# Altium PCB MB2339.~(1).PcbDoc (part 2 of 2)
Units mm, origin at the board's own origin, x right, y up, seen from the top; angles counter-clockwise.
Board outline 43 x 47 mm, 4 copper layers (Top Layer, Signal Layer 1, Signal Layer 2, Bottom Layer), stack 1.539 mm thick; 100 components, 80 nets, 370 pads, 542 vias.

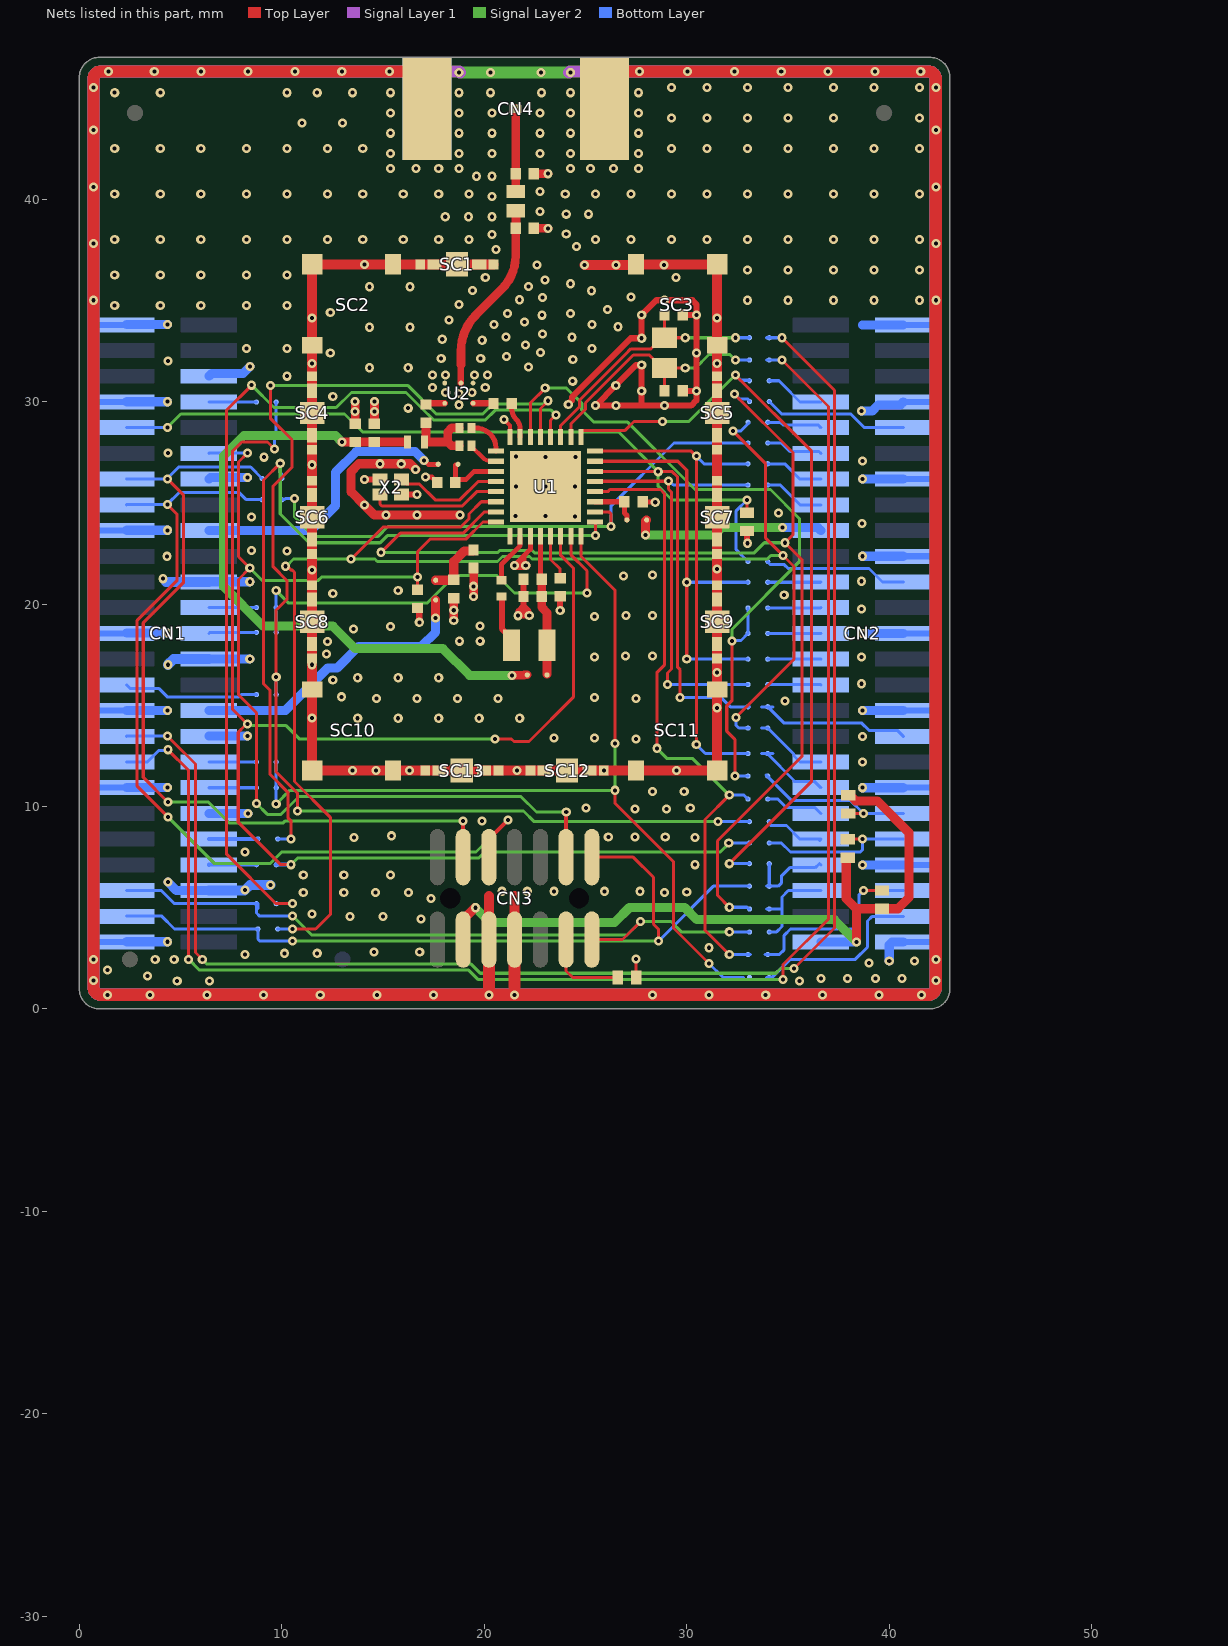
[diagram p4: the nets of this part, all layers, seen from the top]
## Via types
v1: diameter 0.45, hole 0.2, Top Layer to Bottom Layer, tented both sides, 542 vias

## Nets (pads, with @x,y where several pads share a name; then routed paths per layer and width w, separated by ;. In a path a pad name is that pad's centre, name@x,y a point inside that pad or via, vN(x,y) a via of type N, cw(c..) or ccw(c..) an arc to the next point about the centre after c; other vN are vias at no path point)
GND: C1.1 C2.1 C3.1 C4.2 C7.2 C8.1 C9.1 C10.1 C11.2 C12.1 C13.1 C14.1 C15.1 C16.2 CN1.1 CN1.6 CN1.7 CN1.14 CN1.17 CN1.22 CN1.25 CN1.28 CN1.31 CN1.34 CN1.37 CN1.40 CN1.46 CN1.49 CN2.2 CN2.8 CN2.14 CN2.20 CN2.26 CN2.32 CN2.38 CN2.44 CN2.50 CN3.5 CN3.7 CN4.2 CN4.3 CN4.4 CN4.5 R1.1 R5.1 SC1.1 SC2.1 SC3.1 SC4.1 SC5.1 SC6.1 SC7.1 SC8.1 SC9.1 SC10.1 SC11.1 SC12.1 SC13.1 U1.16 U1.27 U1.33 U2.B1 U2.B3 X2.2 X2.4 | length 913.3
  Top Layer w0.15: R5.1@27.5,1.55 v1(27.5,2.475)
  Top Layer w0.2: v1(20.975,29.12) 21.275,28.82 U1.16@21.275,28.25
  Top Layer w0.25: v1(17.1,26.263) 17.412,26.263 17.52,26.155 17.545,26.155 17.675,26.025 C9.1@17.675,26 ; v1@21.538,21.938 v1(21.5,21.9) 21.5,21.925 21.95,22.375 ; v1(22.05,21.9) 21.95,22 21.95,22.375 ; U1.27@22.275,23.35 22.275,22.7 21.95,22.375 ; C10.1@27.82,25.05 27.832,25.037 28.433,25.037 v1(28.445,25.025)
  Top Layer w0.3: v1@14.085,26.15 X2.4@14.855,26.15 ; X2.2@15.905,25.4 16.675,25.4 v1(16.68,25.405) ; v1(16.791,19.097) C15.1@16.791,19.802 ; C13.1@21.941,21.222 C16.2@21.941,20.372 21.941,19.885 ; v1@22.221,19.422 21.941,19.422 ; v1(22.221,19.428) 22.192,19.457 22.192,19.563 22.187,19.568 22.187,19.639 21.941,19.885 ; v1(23.75,19.67) C12.1@23.75,20.375 ; v1(24.15,29.85) 24.15,29.882 24.325,30.057 24.325,30.216 27.234,33.125 v1(27.775,33.125) v1(27.775,34.275) 28.5,35 v1(28.9,35) 30.275,35 30.475,34.8 v1(30.475,34.275) ; C4.2@29.8,30.525 v1(30.475,30.525) ; C3.1@29.8,34.275 v1(30.475,34.275) ; v1(32.992,23.002) 32.984,23.01 32.984,23.596 R1.1@33.023,23.635 ; 21.941,19.422 21.941,19.885 ; 21.941,19.422 v1(21.662,19.422) 21.69,19.451 21.69,19.557 21.696,19.562 21.696,19.645 21.935,19.885 21.941,19.885 ; 27.7,29.8 27.775,29.875 v1(27.775,30.525) v1(27.775,31.8) 27.766,31.791 27.491,31.791 v1(26.496,30.796) v1(25.5,29.8) v1(26.5,29.8) 27.7,29.8 ; 27.7,29.8 v1(28.9,29.8) 30.214,29.8 30.475,30.061 v1(30.475,30.525) ; v1(30.475,30.525) v1(30.475,32.4) v1(30.475,34.275)
  Top Layer w0.43: C7.2@13.625,28.9 v1(13.625,29.5) v1(13.625,30) ; C8.1@14.575,28.9 v1(14.575,29.5) v1(14.575,30) ; v1(18.493,19.191) v1(18.493,19.691) C14.1@18.493,20.291 ; v1(19.475,20.375) v1(19.475,20.875) C11.2@19.475,21.775 ; C2.1@22.45,38.55 v1(23.155,38.55) ; C1.1@22.45,41.25 v1(23.155,41.25)
  Top Layer w0.45: v1(14.08,26.145) v1@14.085,26.15 ; v1@14.855,26.92 v1(14.85,26.925) ; v1@16.614,26.646 16.335,26.925 v1(15.9,26.925) v1(14.85,26.925) ; v1(18.797,24.393) 18.791,24.387 v1(16.68,24.387) v1(15.155,24.387) 14.58,24.387 v1(14.08,24.887) 13.425,25.542 13.425,26.542 13.809,26.925 v1(14.85,26.925) ; v1(21.5,21.9) v1(22.05,21.9)
  Top Layer w0.5: SC8.1@11.5,20.5 SC6.1@11.5,22.468 SC6.1@11.5,23.178 SC6.1@11.5,24.278 SC6.1@11.5,25.378 SC6.1@11.5,26.088 v1(11.5,26.875) SC4.1@11.5,27.623 SC4.1@11.5,28.333 11.5,29.375 SC4.1@11.5,29.433 SC4.1@11.5,30.533 SC4.1@11.5,31.243 v1(11.5,31.875) SC2.1@11.5,32.775 v1(11.5,34.125) SC2.1@11.5,36.775 SC2.1@15.5,36.775 SC1.1@16.94,36.775 ; 11.5,20.655 11.5,19.555 v1(11.5,17) SC10.1@11.5,15.775 SC10.1@11.5,11.775 SC10.1@15.5,11.775 SC13.1@17.08,11.775 SC13.1@17.79,11.775 SC13.1@18.89,11.775 19.69,11.775 SC13.1@20.7,11.775 23.31,11.775 SC12.1@24.09,11.775 SC12.1@25.19,11.775 SC12.1@25.9,11.775 SC11.1@27.5,11.775 v1(29.5,11.775) SC11.1@31.5,11.775 v1(31.5,14.875) SC11.1@31.5,15.775 v1(31.5,16.625) SC9.1@31.5,17.31 SC9.1@31.5,20.22 v1(31.5,21.725) 31.5,22.464 SC7.1@31.5,22.468 SC7.1@31.5,23.178 SC7.1@31.5,24.278 SC7.1@31.5,25.378 SC7.1@31.5,26.088 SC5.1@31.5,27.623 SC5.1@31.5,28.333 SC5.1@31.5,29.433 SC5.1@31.5,30.533 SC5.1@31.5,31.243 SC3.1@31.5,32.775 v1(31.5,34.125) SC3.1@31.5,36.775 SC3.1@27.5,36.775 ; SC1.1@16.94,36.775 SC1.1@17.55,36.775 SC1.1@18.65,36.775 SC1.1@19.75,36.775 SC1.1@20.46,36.775 ; CN3.5@20.23,3.43 20.23,5.575 ; CN3.7@21.5,3.43 21.5,5.575 ; v1(24.95,36.75) v1(26.5,36.75) SC3.1@27.475,36.75
  Top Layer w0.6: CN4.3@17.119,44.46 17.119,45.394 16.212,46.3 v1(15.325,46.3) v1(8.334,46.3) v1(1.446,46.3) 1.075,46.3 ccw(c1.075,45.925) 0.7,45.925 0.7,1.075 ccw(c1.075,1.075) 1.075,0.7 v1(3.5,0.7) v1(17.5,0.7) v1(36.7,0.7) v1(41.6,0.7) 41.925,0.7 ccw(c41.925,1.075) 42.3,1.075 v1(42.3,2.45) 42.3,45.925 ccw(c41.925,45.925) 41.925,46.3 v1(41.554,46.3) v1(39.296,46.3) v1(27.675,46.3) 26.788,46.3 25.881,45.394 CN4.2@25.881,44.46 ; v1(20.225,0.7) 20.23,0.705 CN3.5@20.23,3.43 ; v1(21.5,0.7) CN3.7@21.5,3.43
  Signal Layer 1 w0.6: v1@18.8,46.25 18.75,46.3 v1(15.325,46.3) v1(10.649,46.3) v1(1.446,46.3) 1.075,46.3 ccw(c1.075,45.925) 0.7,45.925 v1(0.7,45.5) 0.7,1.075 ccw(c1.075,1.075) 1.075,0.7 v1(3.5,0.7) v1(17.5,0.7) v1(36.7,0.7) v1(41.6,0.7) 41.925,0.7 ccw(c41.925,1.075) 42.3,1.075 v1(42.3,2.45) 42.3,45.925 ccw(c41.925,45.925) 41.925,46.3 v1(41.554,46.3) v1(27.675,46.3) 24.25,46.3 v1@24.2,46.25
  Signal Layer 2 w0.45: v1(13.5,11.775) v1(14.65,11.775) v1(16.3,11.775)
  Signal Layer 2 w0.6: 0.7,1.075 ccw(c1.075,1.075) 1.075,0.7 v1(3.5,0.7) v1(17.5,0.7) v1(21.5,0.7) v1(36.7,0.7) v1(41.6,0.7) 41.925,0.7 ccw(c41.925,1.075) 42.3,1.075 v1(42.3,2.45) 42.3,45.925 ccw(c41.925,45.925) 41.925,46.3 v1(41.554,46.3) v1(39.296,46.3) v1(34.666,46.3) v1(27.675,46.3) 24.25,46.3 24.2,46.25 v1(22.8,46.25) v1(20.3,46.25) 18.8,46.25 18.75,46.3 v1(15.325,46.3) v1(10.649,46.3) v1(1.446,46.3) 1.075,46.3 ccw(c1.075,45.925) 0.7,45.925 0.7,1.075
  Bottom Layer w0.3: v1(0.7,2.45) 0.7,2.491 0.55,2.641 0.55,3.308 ; v1(0.7,35) 0.7,34.959 0.55,34.809 0.55,33.788 ; CN1.49@2.331,3.308 0.55,3.308 ; CN1.37@2.331,10.928 0.55,10.928 ; CN1.31@2.331,14.738 0.55,14.738 ; CN1.25@2.331,18.548 0.55,18.548 ; CN1.17@2.331,23.628 0.55,23.628 ; CN1.7@2.331,29.978 0.55,29.978 ; CN1.1@2.331,33.788 0.55,33.788 ; v1(4.125,21.25) 4.287,21.088 ; CN2.50@40.691,3.308 42.45,3.308 ; CN2.44@40.691,7.118 42.45,7.118 ; CN2.38@40.691,10.928 42.45,10.928 ; CN2.32@40.691,14.738 42.45,14.738 ; CN2.26@40.691,18.548 42.45,18.548 ; CN2.20@40.691,22.358 42.45,22.358 ; CN2.14@40.691,26.168 42.45,26.168 ; CN2.8@40.691,29.978 42.45,29.978 ; CN2.2@40.691,33.788 42.45,33.788 ; v1(42.3,2.45) 42.3,2.491 42.45,2.641 42.45,3.308 ; v1(42.3,35) 42.329,34.971 42.329,34.821 42.45,34.7 42.45,33.788 ; 0.55,3.308 0.55,10.928 ; 0.55,10.928 0.55,14.738 ; 0.55,14.738 0.55,18.548 ; 0.55,18.548 0.55,23.628 ; 0.55,23.628 0.55,29.978 ; 0.55,29.978 0.55,33.788 ; 42.45,3.308 42.45,7.118 ; 42.45,7.118 42.45,10.928 ; 42.45,10.928 42.45,14.738 ; 42.45,14.738 42.45,18.548 ; 42.45,18.548 42.45,22.358 ; 42.45,22.358 42.45,26.168 ; 42.45,26.168 42.45,29.978 ; 42.45,29.978 42.45,33.788
  Bottom Layer w0.45: CN1.49@2.343,3.32 v1(4.35,3.32) ; CN1.37@2.343,10.94 v1(4.35,10.94) ; CN1.31@2.343,14.75 v1(4.35,14.75) ; CN1.25@2.343,18.56 v1(4.35,18.56) ; CN1.17@2.343,23.64 v1(4.35,23.64) ; CN1.7@2.343,29.99 v1(4.35,29.99) ; CN1.1@2.343,33.8 v1(4.35,33.8) ; v1(4.375,6.275) 4.802,5.848 CN1.46@6.401,5.848 ; CN1.40@6.401,9.658 8.317,9.658 v1(8.325,9.65) ; CN1.14@6.401,26.168 6.483,26.25 v1(8.309,26.25) ; CN1.34@6.408,13.475 v1(8.3,13.475) ; CN1.28@6.413,17.29 v1(8.42,17.29) ; CN1.22@6.413,21.1 v1(8.42,21.1) ; CN1.6@6.413,31.26 6.546,31.393 8.093,31.393 v1(8.425,31.725) ; v1(38.637,29.531) 39.162,29.531 39.464,29.833 40.546,29.833 CN2.8@40.691,29.978 ; 38.672,33.776 CN2.2@40.679,33.776 ; v1(38.684,7.118) CN2.44@40.691,7.118 ; v1(38.684,10.928) CN2.38@40.691,10.928 ; v1(38.684,14.738) CN2.32@40.691,14.738 ; v1(38.684,18.548) CN2.26@40.691,18.548 ; v1(38.684,22.358) CN2.20@40.691,22.358 ; v1(38.684,26.168) CN2.14@40.691,26.168 ; v1(40,2.375) 40,3.163 40.145,3.308 CN2.50@40.691,3.308
  Bottom Layer w0.5: 4.287,21.088 CN1.22@6.401,21.088 ; v1(4.375,17) 4.653,17.278 CN1.28@6.401,17.278 ; CN1.46@6.401,5.848 8.16,5.848 v1(8.187,5.875) 8.437,6.125 v1(9.437,6.125)
  Bottom Layer w0.6: v1(0.7,1.4) v1(0.7,2.45) ; v1@0.7,1.465 0.7,1.075 ccw(c1.075,1.075) 1.075,0.7 v1(3.5,0.7) v1(9.1,0.7) v1(17.5,0.7) v1(36.7,0.7) v1(41.6,0.7) 41.925,0.7 ccw(c41.925,1.075) 42.3,1.075 v1(42.3,1.4) v1(42.3,2.45) ; v1(0.7,35) v1(0.7,45.5) 0.7,45.925 cw(c1.075,45.925) 1.075,46.3 v1(1.446,46.3) v1(15.325,46.3) 16.212,46.3 17.119,45.394 CN4.4@17.119,44.46 ; CN4.5@25.881,44.46 25.881,45.394 26.788,46.3 v1(27.675,46.3) v1(34.666,46.3) v1(39.296,46.3) v1(41.554,46.3) 41.925,46.3 cw(c41.925,45.925) 42.3,45.925 v1(42.3,43.4) v1(42.3,37.8) v1(42.3,35)
  other v1: 1.4,0.7 6.3,0.7 11.9,0.7 14.7,0.7 28.3,0.7 31.1,0.7 33.9,0.7 39.5,0.7 4.836,1.39 6.438,1.375 35.562,1.375 36.625,1.5 37.938,1.5 39.312,1.5 40.625,1.5 3.375,1.625 1.4,1.924 39,2.275 41.25,2.375 3.75,2.438 4.687,2.438 8.187,2.688 10.125,2.75 11.75,2.75 14.563,2.812 16.812,2.812 31.1,3.025 16.875,4.437 13.375,4.563 15,4.563 11.5,4.687 17.378,5.465 11.063,5.75 13.063,5.75 14.625,5.75 16.25,5.75 28.9,5.75 30,5.775 20.875,5.813 22.125,5.813 23.437,5.813 25.937,5.813 27.688,5.813 11.063,6.625 13.063,6.625 15.375,6.625 30.4,7.125 8.187,7.75 13.576,8.471 30.4,8.475 26.125,8.5 27.437,8.5 28.938,8.5 15.419,8.553 19.881,9.288 27.437,9.875 29,9.875 25.025,9.918 30.175,9.918 28.313,10.75 29.875,10.75 21.615,11.77 25.904,11.77 38.675,12.2 27.5,13.325 23.45,13.375 25.45,13.375 38.675,13.45 11.5,14.366 13.75,14.357 15.75,14.357 17.75,14.357 19.75,14.357 21.75,14.357 34.854,15.219 14.68,15.325 16.68,15.325 18.68,15.325 20.68,15.325 27.5,15.325 25.45,15.375 12.947,15.418 38.625,16.063 12.519,16.238 13.75,16.357 15.75,16.357 17.75,16.357 25.45,17.375 38.625,17.375 26.975,17.425 28.3,17.437 12.2,17.534 12.25,18.15 18.783,18.162 19.8,18.162 13.551,18.775 15.375,18.897 19.787,18.909 25.45,19.375 27,19.425 28.3,19.437 38.625,19.75 34.813,20.438 12.519,20.525 15.75,20.675 38.625,21.125 26.875,21.375 28.3,21.437 11.487,21.688 4.329,22.357 10.25,22.625 8.5,22.652 38.647,23.971 8.5,24.3 24.475,24.325 21.55,24.35 23.025,24.35 34.532,24.491 21.575,25.8 23.025,25.8 24.475,25.8 16.608,26.64 38.687,27.063 9.129,27.25 23.025,27.25 24.5,27.25 21.575,27.275 4.379,27.458 16.243,29.669 18.748,29.838 12.519,30.251 18.748,30.387 18.097,30.437 19.398,30.437 17.447,30.686 20.048,30.686 24.368,31.003 10.25,31.25 17.445,31.304 18.095,31.304 19.518,31.304 20.168,31.304 14.341,31.668 16.243,31.669 22.185,31.701 31.5,31.875 4.375,32 24.372,32.075 17.874,32.125 19.824,32.125 21.095,32.214 12.395,32.388 22.781,32.415 8.25,32.625 10.25,32.625 25.327,32.625 22.038,32.788 19.899,33.025 17.924,33.075 21.074,33.185 24.325,33.175 22.868,33.331 14.341,33.668 16.341,33.668 26.606,33.693 20.474,33.8 25.327,33.8 21.988,33.923 18.249,34.025 22.849,34.262 21.149,34.35 24.254,34.346 12.395,34.394 26.085,34.55 1.75,34.75 4,34.75 6,34.75 8.25,34.75 10.25,34.75 18.749,34.8 33,35 35,35 37.25,35 39.25,35 41.5,35 21.749,35.025 22.868,35.13 27.238,35.17 19.424,35.475 25.292,35.471 14.341,35.668 16.341,35.668 22.185,35.675 24.254,35.817 22.999,35.993 20.05,36.125 29.475,36.125 1.75,36.25 4,36.25 6,36.25 8.25,36.25 10.25,36.25 33,36.5 35,36.5 37.25,36.5 39.25,36.5 41.5,36.5 22.599,36.75 28.875,36.75 14.085,36.775 20.587,37.503 24.563,37.653 0.7,37.8 1.75,38 4,38 6,38 8.25,38 10.25,38 12.25,38 14,38 16,38 17.75,38 19.25,38 25.5,38 27.25,38 29.25,38 31,38 33,38 35,38 37.25,38 39.25,38 41.5,38 20.375,38.25 24.05,38.275 18.073,39.125 19.224,39.125 20.375,39.125 24.05,39.25 25.15,39.25 22.75,39.375 20.375,40.125 1.75,40.25 4,40.25 6,40.25 8.25,40.25 10.25,40.25 12.25,40.25 14,40.25 16,40.25 17.75,40.25 19.25,40.25 24,40.25 25.5,40.25 27.25,40.25 29.25,40.25 31,40.25 33,40.25 35,40.25 37.25,40.25 39.25,40.25 41.5,40.25 22.75,40.375 0.7,40.6 42.3,40.6 19.625,41.125 20.375,41.125 15.375,41.5 16.625,41.5 17.75,41.5 18.75,41.5 24.25,41.5 25.25,41.5 26.375,41.5 27.625,41.5 15.375,42.25 18.75,42.25 20.375,42.25 22.75,42.25 24.25,42.25 27.625,42.25 1.75,42.5 4,42.5 6,42.5 8.25,42.5 10.25,42.5 12.25,42.5 14,42.5 29.25,42.5 31,42.5 33,42.5 35,42.5 37.25,42.5 39.25,42.5 41.5,42.5 15.375,43.25 18.75,43.25 20.375,43.25 22.75,43.25 24.25,43.25 27.625,43.25 0.7,43.4 11,43.75 13,43.75 29.25,44 31,44 33,44 35,44 37.25,44 41.5,44 15.375,44.25 18.75,44.25 20.375,44.25 22.75,44.25 24.25,44.25 27.625,44.25 1.75,45.25 4,45.25 10.25,45.25 11.75,45.25 13.5,45.25 15.375,45.25 18.75,45.25 20.3,45.25 22.825,45.25 24.25,45.25 27.625,45.25 29.25,45.5 31,45.5 33,45.5 35,45.5 37.25,45.5 39.25,45.5 41.5,45.5 42.3,45.5 18.75,46.25 24.25,46.25 3.704,46.3 6.019,46.3 12.964,46.3 30.036,46.3 32.351,46.3 36.981,46.3
GPIO2: CN1.8 SB11.2 | length 2.4
  Bottom Layer w0.15: CN1.8@6.401,29.978 6.404,29.975 SB11.2@8.75,29.975
GPIO3/BOOT0: CN1.9 R1.2 SB18.2 SB27.2 U1.6 | length 56.1
  Top Layer w0.15: U1.6@25.475,26.55 25.483,26.542 28.583,26.542 v1(28.591,26.534) ; v1@28.606,26.534 29.29,26.534 29.55,26.274 29.55,16.875 29.675,16.75 v1(29.675,15.375) ; v1(32.975,25.135) 32.975,24.685 R1.2@33.16,24.5
  Signal Layer 2 w0.15: v1(4.35,28.72) 5.017,29.387 13.101,29.387 13.989,28.5 26.625,28.5 v1(28.591,26.534) 28.591,25.813 29.269,25.135 v1(32.975,25.135)
  Bottom Layer w0.15: CN1.9@2.331,28.708 2.343,28.72 v1(4.35,28.72) ; v1(29.675,15.375) 31.7,15.375 32.15,14.925 SB27.2@33.025,14.925 SB27.2@33.1,14.925 ; v1(32.975,25.135) 32.443,24.603 32.443,22.682 SB18.2@33.025,22.1
GPIO5/SWDIO: CN1.13 CN3.4 SB15.1 | length 41.7
  Top Layer w0.15: v1(4.35,26.18) 5.136,25.394 5.136,21.046 3.159,19.068 3.159,11.441 v1(4.375,10.225)
  Top Layer w0.2: v1(18.95,9.275) 18.955,9.27 18.955,7.505 CN3.4@18.96,7.5
  Signal Layer 2 w0.15: v1(4.375,10.225) 6.371,10.225 7.421,9.175 10.05,9.175 10.15,9.275 v1(18.95,9.275)
  Bottom Layer w0.15: CN1.13@2.331,26.168 2.343,26.18 v1(4.35,26.18) ; v1@4.35,26.136 v1(4.35,26.18) ; SB15.1@9.025,26.2 8.462,26.763 4.913,26.763 4.35,26.2 v1(4.35,26.18)
GPIO6/SWCLK: CN1.15 CN3.6 SB17.1 | length 45.1
  Top Layer w0.15: v1(4.35,24.91) 4.836,24.424 4.836,21.171 2.859,19.193 2.859,11.006 v1(4.375,9.49)
  Top Layer w0.2: CN3.6@20.23,7.5 20.23,8.386 v1(21.17,9.326)
  Signal Layer 2 w0.15: v1(4.375,9.49) 6.69,7.175 9.421,7.175 9.996,7.75 19.594,7.75 v1(21.17,9.326)
  Bottom Layer w0.15: CN1.15@2.331,24.898 2.343,24.91 v1(4.35,24.91) ; v1@4.35,24.866 v1(4.35,24.91) ; SB17.1@9.025,25.15 8.252,25.15 7.902,25.5 4.92,25.5 4.35,24.93 v1(4.35,24.91)
GPIO11: CN1.24 SB20.2 | length 2.4
  Bottom Layer w0.15: CN1.24@6.401,19.818 6.408,19.825 SB20.2@8.75,19.825
GPIO12: CN1.26 SB22.2 | length 2.4
  Bottom Layer w0.15: CN1.26@6.401,18.548 6.453,18.6 SB22.2@8.75,18.6
GPIO14: CN1.29 SB26.2 | length 6.7
  Bottom Layer w0.15: CN1.29@2.331,16.008 2.504,15.835 3.921,15.835 4.343,15.413 7.889,15.413 8.001,15.525 8.738,15.525 8.75,15.513 SB26.2@8.75,15.525
GPIO15/OSC32_IN: CN1.33 SB7.2 | length 77.1
  Top Layer w0.15: v1(4.35,13.48) 4.725,13.105 5.736,12.094 5.736,2.789 v1(6.075,2.45) ; v1(34.7,33.15) 37.3,30.55 37.3,4 v1(35.3,2)
  Signal Layer 2 w0.15: v1(6.075,2.45) 6.31,2.215 19.354,2.215 19.804,1.765 34.398,1.765 34.633,2 v1(35.3,2)
  Bottom Layer w0.15: CN1.33@2.331,13.468 2.343,13.48 v1(4.35,13.48) ; SB7.2@33.948,33.15 SB7.2@34.023,33.15 ; SB7.2@34.075,33.15 v1(34.7,33.15)
GPIO16/OSC32_OUT: CN1.35 SB8.2 | length 76
  Top Layer w0.15: v1(4.375,12.805) 5.4,11.78 v1(5.4,2.45) ; v1(34.7,32.05) 37,29.75 37,4.437 34.757,2.194 v1(34.757,1.465)
  Signal Layer 2 w0.15: v1(5.4,2.45) 5.935,1.915 19.229,1.915 19.679,1.465 v1(34.757,1.465)
  Bottom Layer w0.15: CN1.35@2.331,12.198 3.356,12.198 3.925,12.767 4.337,12.767 v1(4.375,12.805) ; SB8.2@33.948,32.05 SB8.2@34.023,32.05 ; SB8.2@34.075,32.05 v1(34.7,32.05)
GPIO17: CN1.36 SB30.2 | length 2.3
  Bottom Layer w0.15: CN1.36@6.401,12.198 6.403,12.2 SB30.2@8.75,12.2
GPIO18: CN1.38 SB32.2 | length 2.4
  Bottom Layer w0.15: CN1.38@6.401,10.928 6.404,10.925 SB32.2@8.75,10.925
GPIO21: CN1.42 SB35.1 | length 2.4
  Bottom Layer w0.2: CN1.42@6.401,8.388 6.413,8.4 SB35.1@8.825,8.4
GPIO22: CN1.44 SB38.2 | length 2.4
  Bottom Layer w0.2: CN1.44@6.401,7.118 6.408,7.125 SB38.2@8.75,7.125
GPIO23/VCP1_RX: CN1.45 CN3.13 SB40.2 SB43.1 | length 35.5
  Top Layer w0.15: CN3.13@25.315,3.425 CN3.13@25.31,3.43 26.83,3.43 v1(27.725,4.325)
  Signal Layer 2 w0.15: v1(10.525,4.6) 11.475,3.65 27.05,3.65 v1(27.725,4.325) 29.22,4.325 29.732,3.812 v1(32.1,3.812)
  Bottom Layer w0.15: CN1.45@2.331,5.848 4.052,5.848 4.7,5.2 SB40.2@8.75,5.2 ; 8.835,4.974 8.835,5.19 8.825,5.2 SB40.2@8.75,5.2 ; v1(10.525,4.6) 10.523,4.598 8.888,4.598 8.75,4.736 SB40.2@8.75,5.2 ; v1(32.1,3.812) SB43.1@33.1,3.812
GPIO24/VCP1_TX: CN1.47 CN3.14 SB39.1 SB42.1 | length 39.6
  Top Layer w0.15: CN3.14@25.31,7.5 27.357,7.5 28.354,6.503 28.354,4.186 28.6,3.94 v1(28.6,3.35)
  Signal Layer 2 w0.15: v1(10.525,3.35) v1(28.6,3.35)
  Bottom Layer w0.15: CN1.47@2.331,4.598 4.052,4.598 4.7,3.95 SB42.1@8.825,3.95 ; 8.835,3.724 8.835,3.94 SB42.1@8.825,3.95 ; v1(10.525,3.35) 10.523,3.348 8.928,3.348 8.825,3.451 SB42.1@8.825,3.95 ; v1(28.6,3.35) 31.313,6.062 SB39.1@33.1,6.062
GPIO28: CN2.7 SB9.2 | length 3
  Bottom Layer w0.15: SB9.2@34.075,31.025 34.553,31.025 34.725,30.853 34.725,30.849 35.596,29.978 CN2.7@36.621,29.978
GPIO29: CN2.9 SB12.1 | length 2.7
  Bottom Layer w0.15: SB12.1@34,28.975 34.623,28.975 34.75,28.848 36.481,28.848 CN2.9@36.621,28.708
GPIO30: CN2.10 SB10.2 | length 7.2
  Bottom Layer w0.15: SB10.2@34.075,30 34.692,29.383 38.102,29.383 38.777,28.708 CN2.10@40.691,28.708
GPIO31: CN2.11 SB13.1 | length 2.8
  Bottom Layer w0.15: SB13.1@34,27.95 34.669,27.95 35.089,27.53 36.529,27.53 CN2.11@36.621,27.438
GPIO33: CN2.13 SB14.1 | length 2.9
  Bottom Layer w0.15: SB14.1@34,26.925 34.839,26.925 35.596,26.168 CN2.13@36.621,26.168
GPIO34: CN2.15 SB16.1 | length 3
  Bottom Layer w0.15: SB16.1@34,25.875 34.618,25.875 34.818,25.675 ; 34.819,25.675 35.596,24.898 CN2.15@36.621,24.898
GPIO37: CN2.21 SB19.1 | length 2.6
  Bottom Layer w0.15: SB19.1@34,21.075 36.608,21.075 CN2.21@36.621,21.088
GPIO39: CN2.23 SB21.1 | length 2.6
  Bottom Layer w0.15: SB21.1@34,19.808 36.611,19.808 CN2.23@36.621,19.818
GPIO41: CN2.25 SB23.1 | length 2.6
  Bottom Layer w0.15: SB23.1@34,18.55 36.619,18.55 CN2.25@36.621,18.548
GPIO42: CN2.27 SB24.1 | length 2.6
  Bottom Layer w0.15: SB24.1@34,17.275 36.618,17.275 CN2.27@36.621,17.278
GPIO44: CN2.29 SB25.1 | length 2.6
  Bottom Layer w0.15: SB25.1@34,16.025 36.604,16.025 CN2.29@36.621,16.008
GPIO47: CN2.35 SB28.1 | length 3.7
  Bottom Layer w0.15: 33.7,13.875 SB28.1@34,13.875 35.301,12.574 35.301,12.493 35.596,12.198 CN2.35@36.621,12.198
GPIO49: CN2.37 SB29.1 | length 3.9
  Bottom Layer w0.15: 33.7,12.612 SB29.1@33.973,12.612 ; 34.247,12.612 SB29.1@34,12.612 SB29.1@33.973,12.612 ; CN2.37@36.621,10.928 36.326,11.223 35.301,11.223 35.301,11.285 SB29.1@33.973,12.612
GPIO50: CN2.39 SB33.1 | length 2.9
  Bottom Layer w0.15: SB33.1@34,10.362 34.503,10.362 34.912,9.953 36.326,9.953 CN2.39@36.621,9.658
GPIO51: CN2.40 R2.1 SB31.1 | length 8.3
  Top Layer w0.15: R2.1@37.975,9.65 v1(38.725,9.65)
  Bottom Layer w0.15: SB31.1@33.919,11.546 35.162,10.304 38.071,10.304 v1(38.725,9.65) 40.683,9.65 CN2.40@40.691,9.658
GPIO52: CN2.41 SB34.2 | length 3.1
  Bottom Layer w0.15: SB34.2@34.075,9.25 34.087,9.238 34.087,9.138 34.1,9.125 34.1,9.11 34.148,9.063 34.921,9.063 35.596,8.388 CN2.41@36.621,8.388 CN2.41@36.546,8.313
GPIO53: CN2.42 R3.1 SB36.2 | length 8.1
  Top Layer w0.15: R3.1@37.95,8.375 37.963,8.388 v1(38.684,8.388)
  Bottom Layer w0.15: SB36.2@34.075,8.2 34.669,8.2 35.119,7.75 38.575,7.75 38.684,7.859 v1(38.684,8.388) CN2.42@40.691,8.388
GPIO54: CN2.43 SB37.2 SB39.2 | length 4.4
  Bottom Layer w0.15: SB39.2@33.948,6.062 SB39.2@34.075,6.062 34.513,6.062 34.687,6.237 34.687,6.579 35.089,6.981 36.345,6.981 36.552,7.187 CN2.43@36.621,7.118 ; 34.075,6.189 SB37.2@34.075,7.175
GPIO55: CN2.45 SB41.2 SB43.2 | length 5
  Bottom Layer w0.15: SB41.2@33.948,4.938 SB41.2@34.075,4.938 34.687,4.938 34.7,4.95 ; SB43.2@34.075,3.812 34.439,3.812 34.7,4.073 34.7,4.95 ; CN2.45@36.621,5.848 35.018,5.848 34.7,5.53 34.7,4.95
GPIO56: CN2.46 R4.1 SB44.1 | length 10.3
  Top Layer w0.15: v1(38.723,5.848) 39.648,5.848 R4.1@39.65,5.85
  Bottom Layer w0.15: SB44.1@33.873,2.688 SB44.1@34,2.688 34.569,2.688 34.813,2.931 34.813,3.637 35.125,3.95 38.237,3.95 38.517,4.23 38.517,5.642 v1(38.723,5.848) CN2.46@40.691,5.848
GPIO57: CN2.48 SB45.2 | length 8.7
  Bottom Layer w0.15: SB45.2@33.948,1.562 SB45.2@34.075,1.562 34.218,1.562 35.106,2.45 38.325,2.45 38.925,3.05 38.925,4.341 39.162,4.578 CN2.48@40.691,4.578
NetC1_2: C1.2 CN4.1 L1.2 | length 4.1
  Top Layer w0.43: L1.2@21.55,40.35 C1.2@21.55,41.25 CN4.1@21.55,44.46
NetC2_2: C2.2 L1.1 U2.B2 | length 9.4
  Top Layer w0.32: U2.B2@18.848,30.911 18.848,31.801
  Top Layer w0.43: 18.848,31.821 18.848,32.487 cw(c21.388,32.487) 19.592,34.283 20.88,35.571 ccw(c19.263,37.188) 21.55,37.188 21.55,37.775 C2.2@21.55,38.55 ; C2.2@21.562,38.55 L1.1@21.562,39.425
NetC3_2: C3.2 SB7.1 U1.11 X1.1 | length 13.2
  Top Layer w0.15: U1.11@23.775,28.25 23.775,28.814 24.7,29.739 24.7,30.061 26.988,32.348 27.239,32.6 28.237,32.6 28.35,32.713 28.35,32.725 28.775,33.15 X1.1@28.9,33.15 ; C3.2@28.9,34.275 X1.1@28.9,33.15 ; v1@30.075,33.15 X1.1@28.9,33.15
  Signal Layer 2 w0.15: v1(29.925,33.15) v1(32.4,33.15)
  Bottom Layer w0.15: v1(32.4,33.15) SB7.1@33.1,33.15
NetC4_1: C4.1 SB8.1 U1.10 X1.2 | length 12.9
  Top Layer w0.15: U1.10@24.275,28.25 24.275,28.89 25,29.615 25,29.936 27.364,32.3 28.149,32.3 28.35,32.099 28.35,32.075 28.775,31.65 X1.2@28.9,31.65 ; C4.1@28.9,30.525 X1.2@28.9,31.65 ; v1(29.925,31.65) X1.2@28.9,31.65
  Signal Layer 2 w0.15: v1(29.925,31.65) 30.425,31.65 31.1,32.325 32.125,32.325 v1(32.4,32.05)
  Bottom Layer w0.15: v1(32.4,32.05) SB8.1@33.1,32.05
NetC5_1: C5.1 U1.15 | length 1.8
  Top Layer w0.25: C5.1@21.356,29.902 21.356,29.654 ccw(c22.104,29.654) 21.575,29.125 cw(c21.092,28.642) 21.775,28.642 U1.15@21.775,28.25
NetC5_2: C5.2 U2.A3 | length 1
  Top Layer w0.32: U2.A3@19.448,29.911 20.445,29.912 C5.2@20.456,29.902
NetC6_1: C6.1 U2.A1 | length 0.8
  Top Layer w0.25: U2.A1@18.034,29.898 U2.A1@18.048,29.912
  Top Layer w0.32: C6.1@17.257,29.852 17.317,29.912 U2.A1@18.048,29.912
NetC6_2: C6.2 L2.2 SB1.2 SB2.2 | length 3.5
  Top Layer w0.43: L2.2@17.125,28.114 C6.2@17.125,28.955 ; 17.266,28.009 17.275,28 18.193,28 ; SB2.2@18.75,27.813 18.38,27.813 18.193,28 ; SB1.2@18.75,28.7 18.401,28.7 18.193,28.492 18.193,28
NetC9_2: C9.2 SB3.1 U1.19 | length 3.1
  Top Layer w0.25: 18.575,26.875 C9.2@18.575,26 18.575,26.025 18.705,26.155 19.105,26.155 19.5,26.55 U1.19@20.575,26.55
NetC10_2: C10.2 SB4.1 U1.3 | length 2.4
  Top Layer w0.25: U1.3@25.475,25.05 C10.2@26.92,25.05 26.92,24.495 27.044,24.371 SB4.1@27.044,24.151
NetC11_1: C11.1 C14.2 SB5.2 U1.25 | length 3
  Top Layer w0.45: SB5.2@17.6,21.175 18.478,21.175 C14.2@18.493,21.191 18.493,22.093 19.026,22.625 19.45,22.625 19.475,22.65 C11.1@19.475,22.675
NetC12_2: C12.2 U1.29 | length 2.3
  Top Layer w0.15: U1.29@23.275,23.35 23.275,22.202 23.75,21.727 C12.2@23.75,21.275
NetC13_2: C13.2 C16.1 L4.1 SB6.2 U1.28 | length 7.7
  Top Layer w0.25: C16.1@22.775,20.538 U1.28@22.775,23.35 ; C13.2@22.775,21.288 C13.2@22.841,21.222
  Top Layer w0.43: C13.2@22.841,21.222 C16.1@22.841,20.372 22.841,19.833 23.1,19.574 L4.1@23.1,17.959 SB6.2@23.1,16.525
NetCN2_22: CN2.22 SB18.1 | length 7.1
  Bottom Layer w0.15: SB18.1@34,22.1 34,22.072 34.132,21.94 34.82,21.94 35.009,21.75 39.004,21.75 39.666,21.088 CN2.22@40.691,21.088
NetCN2_34: CN2.34 SB27.1 | length 7.8
  Bottom Layer w0.15: 33.7,14.925 SB27.1@34,14.925 ; 34.25,14.925 SB27.1@34,14.925 ; CN2.34@40.691,13.468 40.396,13.763 38.998,13.763 38.647,14.114 34.811,14.114 SB27.1@34,14.925
NetCN3_11: CN3.11 R5.2 | length 4.2
  Top Layer w0.15: CN3.11@24.04,3.43 24.04,1.878 24.368,1.55 R5.2@26.6,1.55
NetL3_1: L3.1 L4.2 | length 2.6
  Top Layer w0.3: L3.1@20.866,20.322 20.866,18.784 21.066,18.584 21.075,18.584 21.35,18.309 L4.2@21.35,17.959
NetL3_2: L3.2 U1.26 | length 2.6
  Top Layer w0.25: L3.2@20.85,21.175 20.85,21.957 21.775,22.882 U1.26@21.775,23.35
NetSB1_1: SB1.1 U1.17 | length 1.9
  Top Layer w0.25: SB1.1@19.375,28.7 19.528,28.7 cw(c19.528,27.59) 20.312,28.375 cw(c19.679,27.741) 20.575,27.741 U1.17@20.575,27.55
NetSB2_1: SB2.1 U1.18 | length 1.5
  Top Layer w0.2: SB2.1@19.373,27.813 ccw(c19.46,27.813) 19.399,27.751 19.925,27.225 ccw(c20.347,27.647) 20.347,27.05 U1.18@20.575,27.05
NetSB9_1: SB9.1 SB37.1 U1.9 | length 38.2
  Top Layer w0.15: U1.9@24.775,28.25 24.775,28.525 24.825,28.575 26.96,28.575 27.398,29.012 v1(28.807,29.012) ; v1(32.1,7.175) 36.15,11.225 36.15,27.564 v1(32.4,31.314)
  Signal Layer 2 w0.15: v1(28.807,29.012) 30.099,29.012 v1(32.4,31.314)
  Bottom Layer w0.15: v1(32.1,7.175) SB37.1@33.1,7.175 ; v1(32.4,31.314) 32.664,31.05 SB9.1@33.1,31.05
NetSB10_1: SB10.1 SB41.1 U1.23 | length 57.7
  Top Layer w0.15: v1(14.907,22.554) 15.853,23.5 18.965,23.5 20.015,24.55 U1.23@20.575,24.55 ; v1(32.1,5.025) 31.515,5.61 31.515,8.303 35.687,12.474 35.687,22.188 v1(34.85,23.025) 35.242,23.417 35.242,27.483 v1(32.35,30.375)
  Signal Layer 2 w0.15: v1(14.907,22.554) 20.68,22.554 20.776,22.65 22.361,22.65 22.486,22.525 33.334,22.525 33.834,23.025 v1(34.85,23.025)
  Bottom Layer w0.15: v1(32.1,5.025) 32.968,5.025 33.055,4.938 SB41.1@33.1,4.938 ; v1(32.35,30.375) 32.593,30.132 32.996,30.132 33.1,30.028 SB10.1@33.1,30
NetSB11_1: SB11.1 SB36.1 SB38.1 U1.30 | length 76.6
  Top Layer w0.15: v1(8.3,14.075) 8.217,13.992 v1@8.208,13.992 ; v1(9.649,27.646) 9.295,28 8.025,28 7.559,27.534 7.559,14.816 8.208,14.167 v1@8.208,13.992 ; v1(10.45,7.125) 9.943,7.125 7.85,9.218 7.85,13.661 8.184,13.995 8.204,13.995 v1@8.208,13.992 ; v1(20.525,13.325) 21.348,13.325 21.466,13.207 22.208,13.207 24.4,15.399 24.4,21.777 23.775,22.402 U1.30@23.775,23.35
  Signal Layer 2 w0.15: v1(8.3,14.075) 8.381,14.075 8.464,13.992 10.216,13.992 10.883,13.325 v1(20.525,13.325) ; v1(10.45,7.125) 10.775,7.45 19.719,7.45 20.019,7.75 31.661,7.75 32.075,8.164 v1(32.075,8.2)
  Bottom Layer w0.15: v1(9.649,27.646) 9.649,28.26 9.725,28.336 SB11.1@9.725,29.975 ; v1(32.075,8.2) SB36.1@33.1,8.2
  Bottom Layer w0.2: SB38.1@9.725,7.125 v1(10.45,7.125)
NetSB12_2: SB12.2 SB28.2 SB42.2 U1.22 | length 73.2
  Top Layer w0.15: v1(10.184,21.865) 10.266,21.865 10.461,21.669 10.519,21.669 10.625,21.563 10.625,11.233 12.395,9.463 12.395,4.67 11.675,3.95 v1(10.525,3.95) ; v1(13.427,22.221) 15.006,23.8 18.84,23.8 19.247,24.207 19.247,24.442 19.855,25.05 U1.22@20.575,25.05 ; v1(32.275,28.55) 33.9,26.925 33.9,23.25 35.3,21.85 35.3,17.275 v1(32.425,14.4)
  Signal Layer 2 w0.15: v1(10.184,21.865) 10.223,21.865 10.58,22.221 v1(13.427,22.221) 14.604,22.221 14.721,22.104 20.654,22.104 20.9,22.35 22.236,22.35 22.361,22.225 33.978,22.225 34.153,22.4 v1(34.75,22.4)
  Bottom Layer w0.15: SB42.2@9.8,3.95 v1(10.525,3.95) ; v1(32.275,28.55) 32.675,28.55 SB12.2@33.062,28.937 ; v1(32.425,14.4) 32.425,14.025 32.575,13.875 SB28.2@33.025,13.875 SB28.2@33.1,13.875
NetSB13_2: SB13.2 SB17.2 U1.2 | length 28.3
  Top Layer w0.15: U1.2@25.475,24.55 26.154,24.55 26.25,24.454 v1(26.25,23.825)
  Signal Layer 2 w0.15: v1(10.625,25.203) 10.625,24.303 11.603,23.325 14.738,23.325 15.237,23.825 v1(26.25,23.825)
  Bottom Layer w0.15: SB17.2@10,25.15 10.02,25.17 10.142,25.17 10.175,25.203 v1(10.625,25.203) ; v1(26.25,23.825) 26.25,24.83 29.37,27.95 SB13.2@33.025,27.95
NetSB14_2: SB14.2 SB29.2 U1.8 | length 24.8
  Top Layer w0.15: U1.8@25.475,27.55 30.225,27.55 v1(30.475,27.3) 30.473,27.298 30.473,13.064 v1(30.47,13.061)
  Bottom Layer w0.15: v1(30.47,13.061) 30.919,12.612 SB29.2@33.025,12.612 ; v1(30.475,27.3) 30.85,26.925 SB14.2@33.025,26.925
NetSB15_2: SB15.2 SB35.2 U1.1 | length 40.4
  Top Layer w0.15: v1(9.925,26.949) 9.1,26.124 9.1,16.058 9.425,15.733 9.425,11.584 10.3,10.709 10.3,9.45 10.45,9.3 v1(10.45,8.4) ; U1.1@25.475,24.05 25.5,24.025 v1(25.5,23.375)
  Signal Layer 2 w0.15: v1(9.925,26.949) 9.925,24.447 11.346,23.025 14.862,23.025 15.212,23.375 v1(25.5,23.375)
  Bottom Layer w0.15: SB35.2@9.8,8.4 v1(10.45,8.4) ; v1(9.925,26.949) 9.925,26.499 9.98,26.444 9.98,26.22 SB15.2@10,26.2
NetSB16_2: SB16.2 SB25.2 U1.5 | length 21.8
  Top Layer w0.15: U1.5@25.475,26.05 25.487,26.062 29.087,26.062 v1(29.1,26.075) 29.1,25.673 29.25,25.523 29.25,16.79 29.05,16.59 v1(29.05,16.025)
  Bottom Layer w0.15: v1(29.05,16.025) SB25.2@33.025,16.025 ; v1(29.1,26.075) 29.138,26.075 29.338,25.875 SB16.2@33.025,25.875
NetSB19_2: SB19.2 SB24.2 U1.7 | length 20.1
  Top Layer w0.15: U1.7@25.475,27.05 29.56,27.05 30,26.61 v1(30,21.075) v1(30,17.275)
  Bottom Layer w0.15: v1(30,17.275) SB24.2@33.025,17.275 ; v1(30,21.075) SB19.2@33.025,21.075
NetSB20_1: SB20.1 SB22.1 U1.31 | length 21.7
  Top Layer w0.15: U1.31@24.275,23.35 24.275,22.437 25.075,21.637 v1(25.075,20.546)
  Signal Layer 2 w0.15: v1(9.725,20.662) 10.344,20.042 17.17,20.042 18.539,21.412 20.627,21.412 21.494,20.546 v1(25.075,20.546)
  Bottom Layer w0.15: SB22.1@9.725,18.6 SB20.1@9.725,19.825 v1(9.725,20.662)
NetSB21_2: SB21.2 SB23.2 SB31.2 U1.14 | length 35.4
  Top Layer w0.15: U1.14@22.275,28.25 22.275,29.924 v1(23.01,30.659) ; v1(32.225,18.175) 32.225,15.223 31.975,14.973 31.975,13.718 32.375,13.318 v1(32.375,11.5)
  Signal Layer 2 w0.15: v1(23.01,30.659) 24.065,30.659 24.814,29.91 24.814,29.585 25.42,28.979 27.083,28.979 30.411,25.651 34.136,25.651 35.562,24.225 35.562,22.082 32.225,18.745 v1(32.225,18.175)
  Bottom Layer w0.15: v1(32.225,18.175) 32.25,18.2 32.675,18.2 SB23.2@33.025,18.55 SB21.2@33.025,19.808 ; v1(32.375,11.5) SB31.2@33.025,11.5
NetSB26_1: SB26.1 SB34.1 U1.13 | length 62.7
  Top Layer w0.15: v1(9.437,30.797) 9.437,29.168 10.5,28.106 10.5,26.754 9.575,25.829 9.575,21.838 10.25,21.163 10.25,20.225 9.725,19.7 v1(9.725,16.4) 9.725,11.708 10.775,10.658 v1(10.775,9.775) ; U1.13@22.775,28.25 22.775,29.658 v1(23.155,30.038)
  Signal Layer 2 w0.15: v1(9.437,30.797) 16.217,30.797 17.627,29.387 19.929,29.387 20.412,29.87 22.917,29.87 23.085,30.038 v1(23.155,30.038) ; v1(10.775,9.775) 10.776,9.776 21.939,9.776 22.465,9.25 v1(31.55,9.25)
  Bottom Layer w0.15: SB26.1@9.725,15.525 v1(9.725,16.4) ; v1(31.55,9.25) SB34.1@33.1,9.25
NetSB30_1: SB30.1 SB32.1 SB45.1 U1.32 | length 44.8
  Top Layer w0.15: U1.32@24.775,23.35 24.775,22.361 26.45,20.687 v1(26.45,13.105) ; v1(26.45,10.8) 26.45,10.174 29.35,7.274 29.35,4 v1(31.1,2.25)
  Signal Layer 2 w0.15: v1(9.725,10.125) 10.4,10.8 v1(26.45,10.8) v1(26.45,13.105)
  Bottom Layer w0.15: v1(9.725,10.125) SB32.1@9.725,10.925 SB30.1@9.725,12.2 ; v1(31.1,2.25) 31.788,1.562 32.8,1.562
NetSB33_2: SB33.2 SB44.2 U1.4 | length 31.7
  Top Layer w0.15: U1.4@25.475,25.55 26.1,25.55 26.2,25.65 28.699,25.65 28.895,25.454 28.895,16.978 28.525,16.608 v1(28.525,12.875) ; v1(32.1,2.688) 30.9,3.888 30.9,9.363 v1(32.1,10.563)
  Signal Layer 2 w0.15: v1(28.525,12.875) 29.037,12.363 30.299,12.363 v1(32.1,10.563)
  Bottom Layer w0.15: v1(32.1,2.688) SB44.2@33.025,2.688 33.152,2.688 ; v1(32.1,10.563) 32.825,10.563 SB33.2@33.025,10.362
NetSB40_1: SB40.1 U1.12 | length 46.6
  Top Layer w0.15: v1(8.512,30.805) 7.259,29.552 7.259,7.66 9.719,5.2 v1(10.525,5.2) ; U1.12@23.275,28.25 23.275,29.069 v1(23.54,29.334)
  Signal Layer 2 w0.15: v1(8.512,30.805) 9.617,29.7 12.689,29.7 13.439,30.45 16.138,30.45 17.2,29.387 17.203,29.387 17.503,29.087 20.054,29.087 20.536,29.57 23.302,29.57 23.539,29.334 v1(23.54,29.334)
  Bottom Layer w0.15: SB40.1@9.725,5.2 v1(10.525,5.2)
NetU1_20: U1.20 X2.3 | length 5.5
  Top Layer w0.15: X2.3@15.905,26.15 16.13,25.925 16.293,25.925 16.796,25.925 17.578,25.143 18.794,25.143 19.701,26.05 U1.20@20.575,26.05
NetU1_21: U1.21 X2.1 | length 6.5
  Top Layer w0.15: X2.1@14.855,25.4 14.855,24.931 14.943,24.843 18.918,24.843 19.625,25.55 U1.21@20.575,25.55
NRST: C15.2 CN1.12 CN3.12 U1.24 | length 53.6
  Top Layer w0.15: v1(8.3,27.45) 7.859,27.009 7.859,22.336 v1(8.42,21.775) 7.859,21.214 7.859,15.514 8.75,14.623 v1(8.75,10.15) ; C15.2@16.7,20.7 v1(16.7,21.339) 16.7,22.579 17.321,23.2 19.089,23.2 19.939,24.05 U1.24@20.575,24.05
  Top Layer w0.2: CN3.12@24.04,7.5 24.045,7.505 24.045,9.72 v1(24.05,9.725)
  Signal Layer 2 w0.15: v1(8.42,21.775) 9.045,21.15 11.78,21.15 11.969,21.339 v1(16.7,21.339) ; v1(8.75,10.15) 9.29,9.61 9.96,9.61 10.848,10.498 21.802,10.498 22.575,9.725 v1(24.05,9.725)
  Bottom Layer w0.15: CN1.12@6.401,27.438 6.413,27.45 v1(8.3,27.45)
VDD: CN2.49 CN3.3 R2.2 R3.2 R4.2 | length 38
  Top Layer w0.45: CN3.3@18.96,3.43 18.96,4.417 19.543,5 v1(19.563,5) ; R3.2@37.95,7.475 37.905,7.475 37.875,7.445 37.875,5.45 38.391,4.934 ; R2.2@37.975,10.55 38.07,10.55 38.34,10.28 39.409,10.28 40.974,8.715 40.974,5.498 40.425,4.95 R4.2@39.65,4.95 38.407,4.95 38.391,4.934 ; v1(38.391,3.308) 38.391,4.934
  Signal Layer 2 w0.45: v1(19.563,5) 20.283,4.28 26.44,4.28 27.172,5.012 29.897,5.012 30.497,4.412 37.287,4.412 v1(38.391,3.308)
  Bottom Layer w0.45: CN2.49@36.621,3.308 v1(38.391,3.308)
VDD_1: CN2.17 SB4.2 | length 9.6
  Top Layer w0.45: v1(27.97,23.4) 27.97,24.1 SB4.2@28.02,24.15
  Signal Layer 2 w0.45: v1(27.97,23.4) 31.358,23.4 31.733,23.775 v1(34.725,23.775)
  Bottom Layer w0.45: v1@34.721,23.779 v1(34.725,23.775) ; v1@34.725,23.779 35.108,23.779 35.114,23.773 36.476,23.773 CN2.17@36.621,23.628
VDDRF: CN1.18 SB3.2 | length 14.2
  Top Layer w0.25: v1(17.029,27.079) 17.057,27.079 17.236,26.9 SB3.2@17.725,26.9
  Bottom Layer w0.45: CN1.18@6.401,23.628 11.428,23.628 12.652,24.852 12.652,26.499 13.678,27.525 16.584,27.525 v1(17.029,27.079)
VDDSD: CN1.32 SB5.1 | length 14.4
  Top Layer w0.45: v1(17.6,19.3) SB5.1@17.6,20.2
  Bottom Layer w0.45: CN1.32@6.413,14.75 10.182,14.75 12.271,16.838 12.734,16.838 13.804,17.908 16.893,17.908 17.6,18.615 v1(17.6,19.3)
VFBSD: C7.1 C8.2 L2.1 SB6.1 | length 32.8
  Top Layer w0.43: v1(12.97,28) 13.594,28 C7.1@13.609,27.984 ; C7.1@13.625,28 C8.2@14.575,28 L2.1@16.12,28 ; v1(21.375,16.475) 21.379,16.479 21.964,16.479 21.985,16.5 SB6.1@22.125,16.5
  Signal Layer 2 w0.45: v1(12.97,28) 12.645,28.325 8.137,28.325 7.125,27.313 7.125,20.863 9.079,18.909 12.519,18.909 13.627,17.8 17.95,17.8 19.275,16.475 v1(21.375,16.475)
pads on no net: CART-1.1 CN1.2 CN1.3 CN1.4 CN1.5 CN1.10 CN1.11 CN1.16 CN1.19 CN1.20 CN1.21 CN1.23 CN1.27 CN1.30 CN1.39 CN1.41 CN1.43 CN1.48 CN1.50 CN2.1 CN2.3 CN2.4 CN2.5 CN2.6 CN2.12 CN2.16 CN2.18 CN2.19 CN2.24 CN2.28 CN2.30 CN2.31 CN2.33 CN2.36 CN2.47 CN3.1 CN3.2 CN3.8 CN3.9 CN3.10 CN3.NPTH1 CN3.NPTH2 MIRE-1.1 MIRE-2.1 MIRE-3.1 MIRE-4.1 MIRE-5.1 MIRE-6.1

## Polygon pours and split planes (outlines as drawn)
GND on Top Layer "GND_L01_P001" (solid, remove dead copper, pour order 1): 0,47 43,47 43,0 0,0
NetC11_1 on Top Layer "NetC18_2" (solid, remove dead copper, pour order 5): 19.225,22.95 20.636,22.95 21.15,23.464 21.15,23.75 21.4,23.75 21.4,22.918 20.882,22.4 19.225,22.4
GND on Signal Layer 1 "GND_L02_P000" (solid, remove dead copper, pour order 0): 0,47 43,47 43,0 0,0
GND on Signal Layer 2 "GND_L03_P002" (solid, remove dead copper, pour order 2): 0,47 43,47 43,0 0,0
GND on Bottom Layer "GND_L04_P003" (solid, remove dead copper, pour order 3): 0,47 43,47 43,0 0,0

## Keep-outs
Top Layer:
  region: 19.037,20.552 19.037,19.211 cw(c18.503,19.211) 18.503,18.677 cw(c18.503,19.202) 17.978,19.202 17.978,20.552 18.128,20.552
  region: 20.009,22.025 20.009,20.684 cw(c19.475,20.684) 19.475,20.15 cw(c19.475,20.675) 18.95,20.675 18.95,22.025 19.1,22.025
  region: 14.155,25.77 14.08,25.77 cw(c14.08,26.15) 13.7,26.15 cw(c14.075,26.15) 14.075,26.525 15.225,26.525 15.225,25.775
  region: 14.041,28.65 14.041,29.991 cw(c14.575,29.991) 14.575,30.525 cw(c14.575,30) 15.1,30 15.1,28.65 14.95,28.65
  region: 13.091,28.65 13.091,29.991 cw(c13.625,29.991) 13.625,30.525 cw(c13.625,30) 14.15,30 14.15,28.65 14,28.65
  region: 21.55,22.862 21.55,23.825 23.5,23.825 23.5,22.275 23.85,21.925 23.85,15.573 23.527,15.25 20.849,15.25 20.125,15.974 20.125,22.075 20.763,22.075
Signal Layer 1:
  region: 20.5,23.025 20.125,22.65 20.125,15.974 20.449,15.65 23.5,15.65 23.85,16 23.85,18.8 23.85,22.675 23.5,23.025
Keep-Out Layer:
  region: 17.134,25.875 17.717,25.875 cw(c17.717,25.717) 17.875,25.717 17.875,24.4 cw(c17.625,24.4) 17.625,24.15 13.834,24.15 13.834,23.95 17.617,23.95 ccw(c17.617,24.408) 18.075,24.408 18.075,25.725 ccw(c17.725,25.725) 17.725,26.075 17.125,26.075 cw(c17.125,26.625) 16.575,26.625 ccw(c15.85,26.625) 15.85,27.35 13.625,27.35 13.625,27.15 15.85,27.15 cw(c15.855,26.62) 16.384,26.625 ccw(c17.134,26.625)

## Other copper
Top Layer:
  region net GND: 18.175,30.183 18.198,30.171 18.22,30.157 18.241,30.141 18.26,30.124 18.278,30.104 18.294,30.083 18.308,30.061 18.32,30.038 18.33,30.014 18.338,29.989 18.343,29.963 18.347,29.938 18.348,29.911 18.348,29.586 19.148,29.586 19.148,29.911 19.149,29.938 19.153,29.963 19.158,29.989 19.166,30.014 19.176,30.038 19.188,30.061 19.202,30.083 19.218,30.104 19.236,30.124 19.255,30.141 19.276,30.157 19.298,30.171 19.321,30.183 19.345,30.193 19.37,30.201 19.396,30.207 19.422,30.21 19.448,30.211 19.773,30.211 19.773,30.411 20.523,30.411 20.523,31.536 19.147,31.536 19.147,30.911 19.146,30.885 19.143,30.859 19.137,30.834 19.129,30.809 19.119,30.785 19.107,30.761 19.093,30.739 19.077,30.719 19.059,30.699 19.04,30.682 19.019,30.666 18.997,30.652 18.974,30.64 18.95,30.629 18.925,30.622 18.899,30.616 18.873,30.613 18.847,30.611 18.821,30.613 18.795,30.616 18.769,30.622 18.744,30.629 18.72,30.64 18.697,30.652 18.675,30.666 18.654,30.682 18.635,30.699 18.617,30.719 18.601,30.739 18.587,30.761 18.575,30.785 18.565,30.809 18.557,30.834 18.552,30.859 18.548,30.885 18.547,30.911 18.547,31.536 16.973,31.536 16.973,30.411 17.723,30.411 17.723,30.211 18.048,30.211 18.074,30.21 18.1,30.207 18.126,30.201 18.151,30.193
  pour cut-out: 21.749,31.877 21.749,28.775 16.565,28.775 16.565,31.877 18.175,31.877 18.175,31.641 19.614,31.641 19.614,31.877
  region net NetC1_2: 21.85,44.26 21.85,44.66 22.054,45.31 22.054,46.98 21.054,46.98 21.054,45.31 21.25,44.66 21.25,44.26
  pour cut-out: 16.166,21.446 20.707,21.446 20.707,19.293 16.166,19.293
  pour cut-out: 28.5,34.837 28.588,34.925 30.193,34.925 30.309,34.809 30.309,29.989 30.313,29.985 30.29,29.962 28.128,29.962 27.924,30.166 27.924,34.262
  pour cut-out: 13.865,26.725 13.617,26.477 13.617,25.638 14.647,24.608 15.261,24.608 15.261,26.723
  text "1" at 4.959,43.768 h1.5
Signal Layer 1:
  pour cut-out: 20.75,47 22.35,47 22.35,44.26 20.75,44.26
  text "2" at 6.181,43.768 h1.5
Signal Layer 2:
  text "3" at 8.065,43.776 h1.5
Bottom Layer:
  text "4" at 9.333,43.769 h1.5
Multi-Layer:
  pour cut-out: 4.5,45 9.75,45 9.75,43.5 4.5,43.5

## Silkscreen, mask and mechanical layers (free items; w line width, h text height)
Top Overlay:
  lines w0.12: 19.353,29.2 19.945,29.2 19.945,28.821 ; 19.363,27.322 19.916,27.322 19.945,27.322 19.945,28.821 ; 24.7,30.525 24.7,28.933 24.6,28.833 19.957,28.833 19.945,28.821
  text "J" at 31.674,41.681 h10
  text "MB2339A" at 30.963,39.013 h2.3
  text "H" at 7.914,38.399 h10
  text "K" at 2.05,38.292 h8
  text "G" at 31.784,7.269 h6
  text "C" at 1.359,6.216 h8
  text "E" at 8.123,6.009 h9
  text "I" at 26.716,4.324 h10
  text "F" at 32.003,2.584 h8
  text "S" at 4.973,1.178 h6
Top Solder:
  rectangle: 4.5,43.5 9.75,45
  lines w0.7: 11.5,20.5 11.5,21.365 11.5,22.464 11.5,23.174 11.5,24.274 11.5,25.374 11.5,26.084 11.5,26.875 11.5,27.565 11.5,28.125 11.5,29.375 ; 11.5,20.655 11.5,19.555 11.5,18.75 11.5,17 11.5,15.775 ; 20.46,36.775 19.75,36.775 18.65,36.775 17.55,36.775 16.94,36.775 16.94,36.775 16.22,36.775 15.5,36.775 14.085,36.775 11.5,36.775 11.5,34.125 11.5,32.775 ; 24.95,36.75 26.5,36.75 27.475,36.75 ; 27.5,36.775 28.875,36.775 31.5,36.775 31.5,34.125 31.5,32.775 ; 11.5,15.775 11.5,14.366 11.5,11.775 13.5,11.775 14.65,11.775 15.5,11.775 16.3,11.775 19.69,11.775 ; 11.5,15.775 11.5,15.775 ; 11.5,29.375 11.5,29.375 ; 11.5,29.375 11.5,30.625 11.5,31.185 11.5,31.875 11.5,32.774 ; 11.5,32.775 11.5,32.774 ; 19.69,11.775 19.69,11.775 ; 19.69,11.775 20.4,11.775 21.5,11.775 22.6,11.775 23.31,11.775 ; 23.31,11.775 23.31,11.775 ; 23.31,11.775 27.5,11.775 29.5,11.775 31.5,11.775 31.5,14.875 31.5,15.775 31.5,16.625 31.5,17.875 31.5,19.75 31.5,22.464 ; 31.5,22.464 31.5,22.464 ; 31.5,22.464 31.5,23.174 31.5,24.274 31.5,25.374 31.5,26.084 31.5,29.5 31.5,30.75 31.5,31.875 31.5,32.774 ; 31.5,32.775 31.5,32.774
Bottom Solder:
  rectangle: 4.5,43.5 9.75,45
M1-Board Shape:
  the board outline again, w0.1
Drill Drawing:
  drawing of 186 lines, arcs and shapes, not listed
  text "PCB SPECIFICATIONS :" at -22.541,97.137 h3
  text "A.   MATERIAL :" at -22.541,93.137 h3
  text "FR-4" at 15.959,93.137 h3
  text "TG-170" at 32.459,93.137 h3
  text "X  TG-150" at 50.709,93.137 h3
  text "TG-140" at 66.709,93.137 h3
  text "B.   MATERIAL FAMILY :" at -22.541,90.137 h3
  text "N/A" at 15.959,90.137 h3
  text "C.   SOLDERMASK COLOR :" at -22.541,87.137 h3
  text "GREEN" at 15.959,87.137 h3
  text "X  BLUE" at 32.459,87.137 h3
  text "RED" at 50.709,87.137 h3
  text "BLACK" at 66.709,87.137 h3
  text "D.   SILKSCREEN COLOR :" at -22.541,84.137 h3
  text "X  WHITE" at 15.959,84.137 h3
  text "YELLOW" at 32.459,84.137 h3
  text "BLACK" at 50.709,84.137 h3
  text "E.   SURFACE FINISH :" at -22.541,81.137 h3
  text "X  ENIG" at 15.959,81.137 h3
  text "IMMERSION SILVER" at 32.459,81.137 h3
  text "IMMERSION TIN" at 66.709,81.137 h3
  text "HASL" at 15.959,78.137 h3
  text "HASL (PB-FREE)" at 32.459,78.137 h3
  text "GOLDEN FINGER" at 66.709,78.137 h3
  text "F.   IMPEDANCE CONTROL :" at -22.541,75.137 h3
  text "NO" at 15.959,75.137 h3
  text "X  YES" at 32.459,75.137 h3
  text "G.   THROUGH VIA :" at -22.541,72.137 h3
  text "PLUG THE VIAS WHICH ARE COVERED WITH SOLDERMASK ONE OR TWO SIDE." at 15.959,72.137 h3
  text "PLUG MATERIAL :" at 15.959,69.137 h3
  text "X  SOLDERMASK" at 41.459,69.137 h3
  text "NON-CONDUCTIVE EPOXY." at 66.709,69.137 h3
  text "H.   STACK-UP :" at -22.541,66.137 h3
  text "SEE LAYER STACK-UP SEQUENCE FOR OVERALL THICKNESS." at 15.959,66.137 h3
  text "Layer" at 50.841,59.1 h1.8
  text "Name" at 58.376,59.1 h1.8
  text "Material" at 72.946,59.1 h1.8
  text "Thickness" at 86.039,59.1 h1.8
  text "Constant" at 96.793,59.1 h1.8
  text "PCB : TYPE 3" at 110.088,57.996 h3
  text "Top Overlay" at 58.376,55.5 h1.8
  text "ASPECT-RATIO, AXE Z :" at 110.088,52.496 h3
  text "Top Solder" at 58.376,51.9 h1.8
  text "Solder Resist" at 72.946,51.9 h1.8
  text "0,015mm" at 86.039,51.9 h1.8
  text "3.5" at 96.793,51.9 h1.8
  text "1" at 50.841,48.3 h1.8
  text "Top Layer" at 58.376,48.3 h1.8
  text "Copper" at 72.946,48.3 h1.8
  text "0,041mm" at 86.039,48.3 h1.8
  text "6 :1 à 8 :1 / LEVEL \"B\"" at 110.107,45.749 h3
  text "Dielectric 1" at 58.376,44.7 h1.8
  text "Core-028" at 72.946,44.7 h1.8
  text "0,254mm" at 86.039,44.7 h1.8
  text "4.4" at 96.793,44.7 h1.8
  text "2" at 50.84,41.1 h1.8
  text "Signal Layer 1" at 58.376,41.1 h1.8
  text "Copper" at 72.946,41.1 h1.8
  text "0,018mm" at 86.039,41.1 h1.8
  text "Dielectric 2" at 58.376,37.5 h1.8
  text "FR4" at 72.946,37.5 h1.8
  text "0,914mm" at 86.039,37.5 h1.8
  text "4.4" at 96.793,37.5 h1.8
  text "3" at 50.841,33.9 h1.8
  text "Signal Layer 2" at 58.376,33.9 h1.8
  text "Copper" at 72.946,33.9 h1.8
  text "0,018mm" at 86.039,33.9 h1.8
  text "MINIMUN PARAMETERS" at 109.5,32.02 h3
  text "Dielectric 3" at 58.376,30.3 h1.8
  text "Core-028" at 72.946,30.3 h1.8
  text "0,254mm" at 86.039,30.3 h1.8
  text "4.4" at 96.793,30.3 h1.8
  text "4" at 50.841,26.7 h1.8
  text "Bottom Layer" at 58.376,26.7 h1.8
  text "Copper" at 72.946,26.7 h1.8
  text "0,041mm" at 86.039,26.7 h1.8
  text "DEFAULT" at 109.5,26.52 h3
  text "Bottom Solder" at 58.376,23.1 h1.8
  text "Solder Resist" at 72.946,23.1 h1.8
  text "0,015mm" at 86.039,23.1 h1.8
  text "3.5" at 96.793,23.1 h1.8
  text "TRACKS : 0.150mm           / GAPS : 0.150mm" at 109.5,20.77 h3
  text "Bottom Overlay" at 58.376,19.5 h1.8
  text "Symbol" at 51.125,12.713 h2.16
  text "Count" at 59.581,12.713 h2.16
  text "Hole Size" at 68.354,12.713 h2.16
  text "Plated" at 83.786,12.713 h2.16
  text "Hole Type" at 91.212,12.713 h2.16
  text "Drill Layer Pair" at 102.018,12.713 h2.16
  text "Via/Pad" at 122.506,12.713 h2.16
  text "Hole Length" at 131.362,12.713 h2.16
  text "542" at 59.581,8.983 h1.8
  text "0.20mm (7.87mil)" at 68.354,8.983 h1.8
  text "PTH" at 83.786,8.983 h1.8
  text "Round" at 91.212,8.983 h1.8
  text "Top Layer - Bottom Layer" at 102.018,8.983 h1.8
  text "Via" at 122.506,8.983 h1.8
  text "-" at 131.362,8.983 h1.8
  text "2" at 59.581,5.253 h1.8
  text "1.00mm (39.37mil)" at 68.354,5.253 h1.8
  text "NPTH" at 83.786,5.253 h1.8
  text "Round" at 91.212,5.253 h1.8
  text "Top Layer - Bottom Layer" at 102.018,5.253 h1.8
  text "Pad" at 122.506,5.253 h1.8
  text "-" at 131.362,5.253 h1.8
  text "544 Total" at 59.581,1.522 h1.8

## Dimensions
1,0 to 1,47 on M2-Board Dimensions
0,1 to 43,1 on M2-Board Dimensions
